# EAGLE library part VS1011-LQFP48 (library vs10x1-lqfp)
VS1011 MP3 Decoder (LQFP-48)

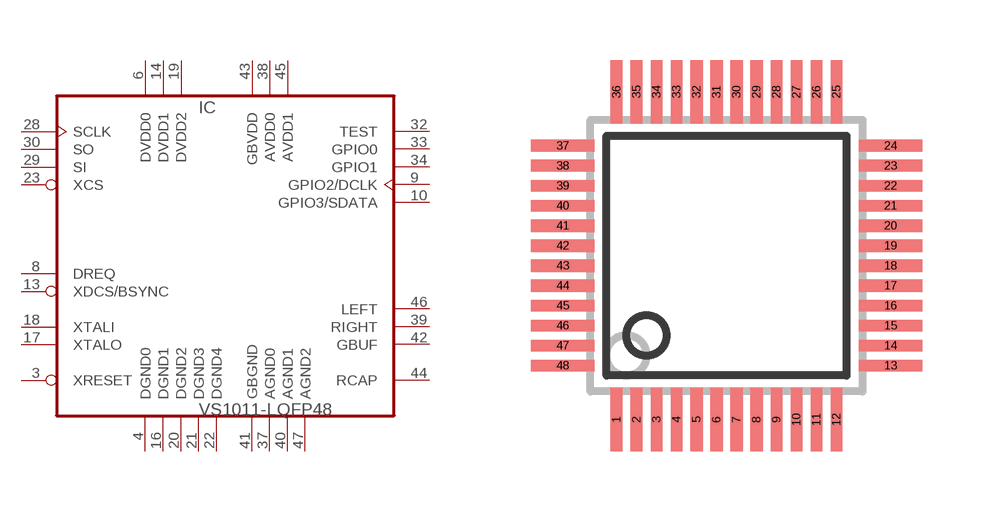
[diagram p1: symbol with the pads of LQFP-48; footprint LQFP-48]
Designator prefix IC

## VS1011-LQFP48  [LQFP-48]
3  XRESET  in
4  DGND0  pwr
6  DVDD0  pwr
8  DREQ  oc
9  GPIO2/DCLK  in
10  GPIO3/SDATA  in
13  XDCS/BSYNC  in
14  DVDD1  pwr
16  DGND1  pwr
17  XTALO  pas
18  XTALI  pas
19  DVDD2  pwr
20  DGND2  pwr
21  DGND3  pwr
22  DGND4  pwr
23  XCS  in
28  SCLK  in
29  SI  in
30  SO  hiz
32  TEST  pas
33  GPIO0  pas
34  GPIO1  pas
37  AGND0  pwr
38  AVDD0  pwr
39  RIGHT  out
40  AGND1  pwr
41  GBGND  pwr
42  GBUF  out
43  GBVDD  pwr
44  RCAP  pas
45  AVDD1  pwr
46  LEFT  out
47  AGND2  pwr

## Footprint LQFP-48 (pad centres in mm)
LQFP-48
smd 0.3 x 1.6: 1 -2.75,-4.1; 2 -2.25,-4.1; 3 -1.75,-4.1; 4 -1.25,-4.1; 5 -0.75,-4.1; 6 -0.25,-4.1; 7 0.25,-4.1; 8 0.75,-4.1; 9 1.25,-4.1; 10 1.75,-4.1; 11 2.25,-4.1; 12 2.75,-4.1; 25 2.75,4.1; 26 2.25,4.1; 27 1.75,4.1; 28 1.25,4.1; 29 0.75,4.1; 30 0.25,4.1; 31 -0.25,4.1; 32 -0.75,4.1; 33 -1.25,4.1; 34 -1.75,4.1; 35 -2.25,4.1; 36 -2.75,4.1
smd 1.6 x 0.3: 13 4.1,-2.75; 14 4.1,-2.25; 15 4.1,-1.75; 16 4.1,-1.25; 17 4.1,-0.75; 18 4.1,-0.25; 19 4.1,0.25; 20 4.1,0.75; 21 4.1,1.25; 22 4.1,1.75; 23 4.1,2.25; 24 4.1,2.75; 37 -4.1,2.75; 38 -4.1,2.25; 39 -4.1,1.75; 40 -4.1,1.25; 41 -4.1,0.75; 42 -4.1,0.25; 43 -4.1,-0.25; 44 -4.1,-0.75; 45 -4.1,-1.25; 46 -4.1,-1.75; 47 -4.1,-2.25; 48 -4.1,-2.75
